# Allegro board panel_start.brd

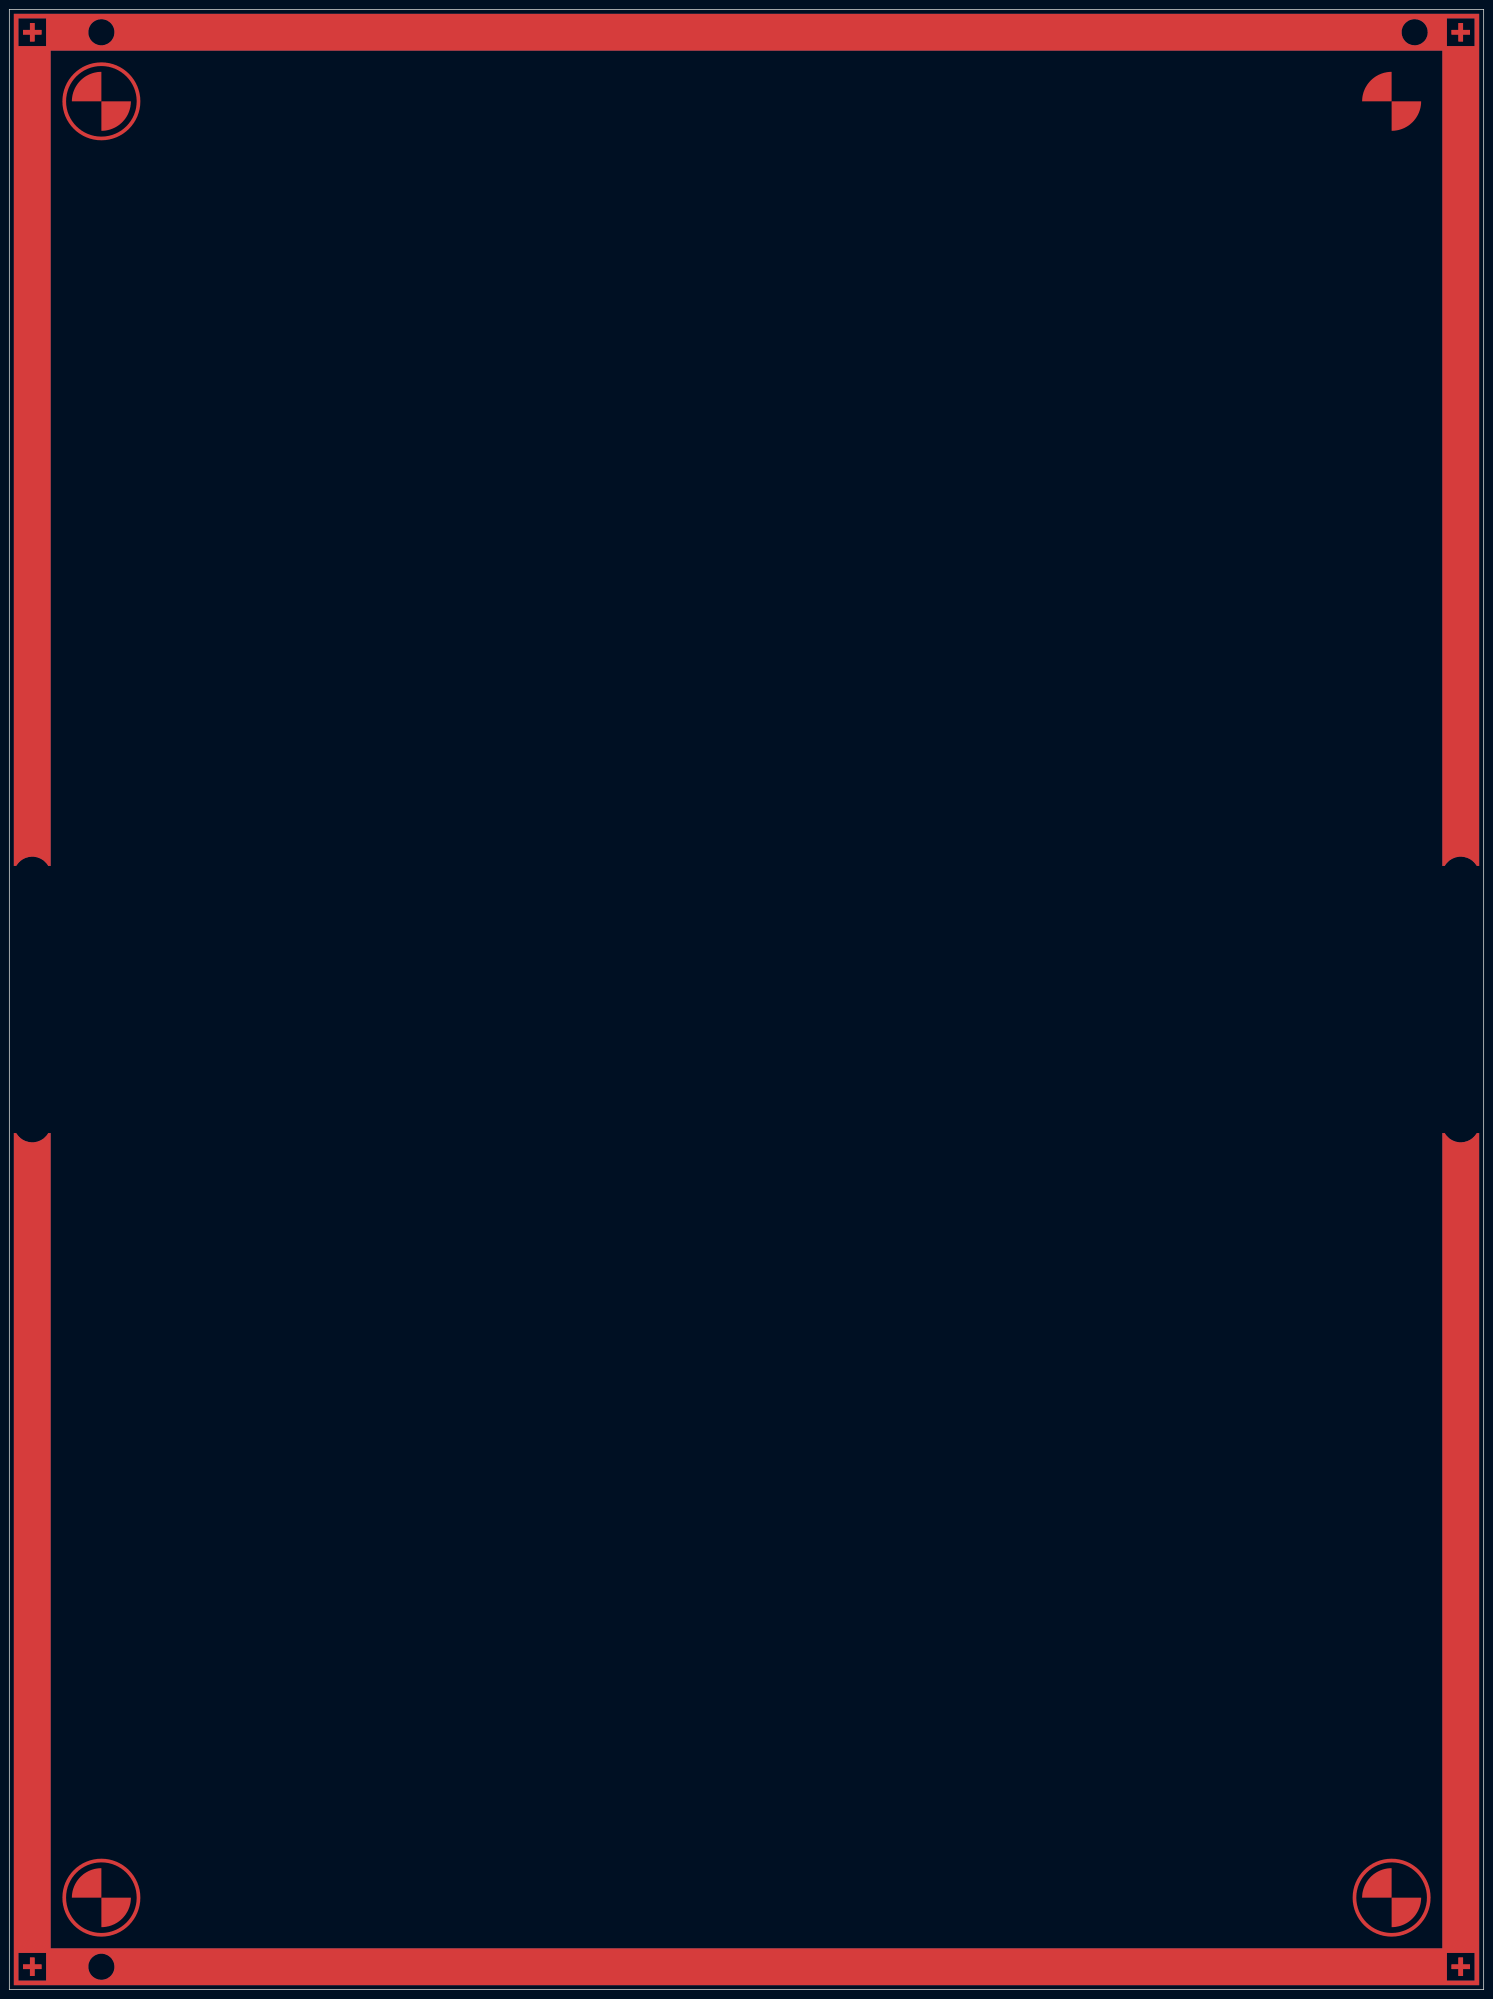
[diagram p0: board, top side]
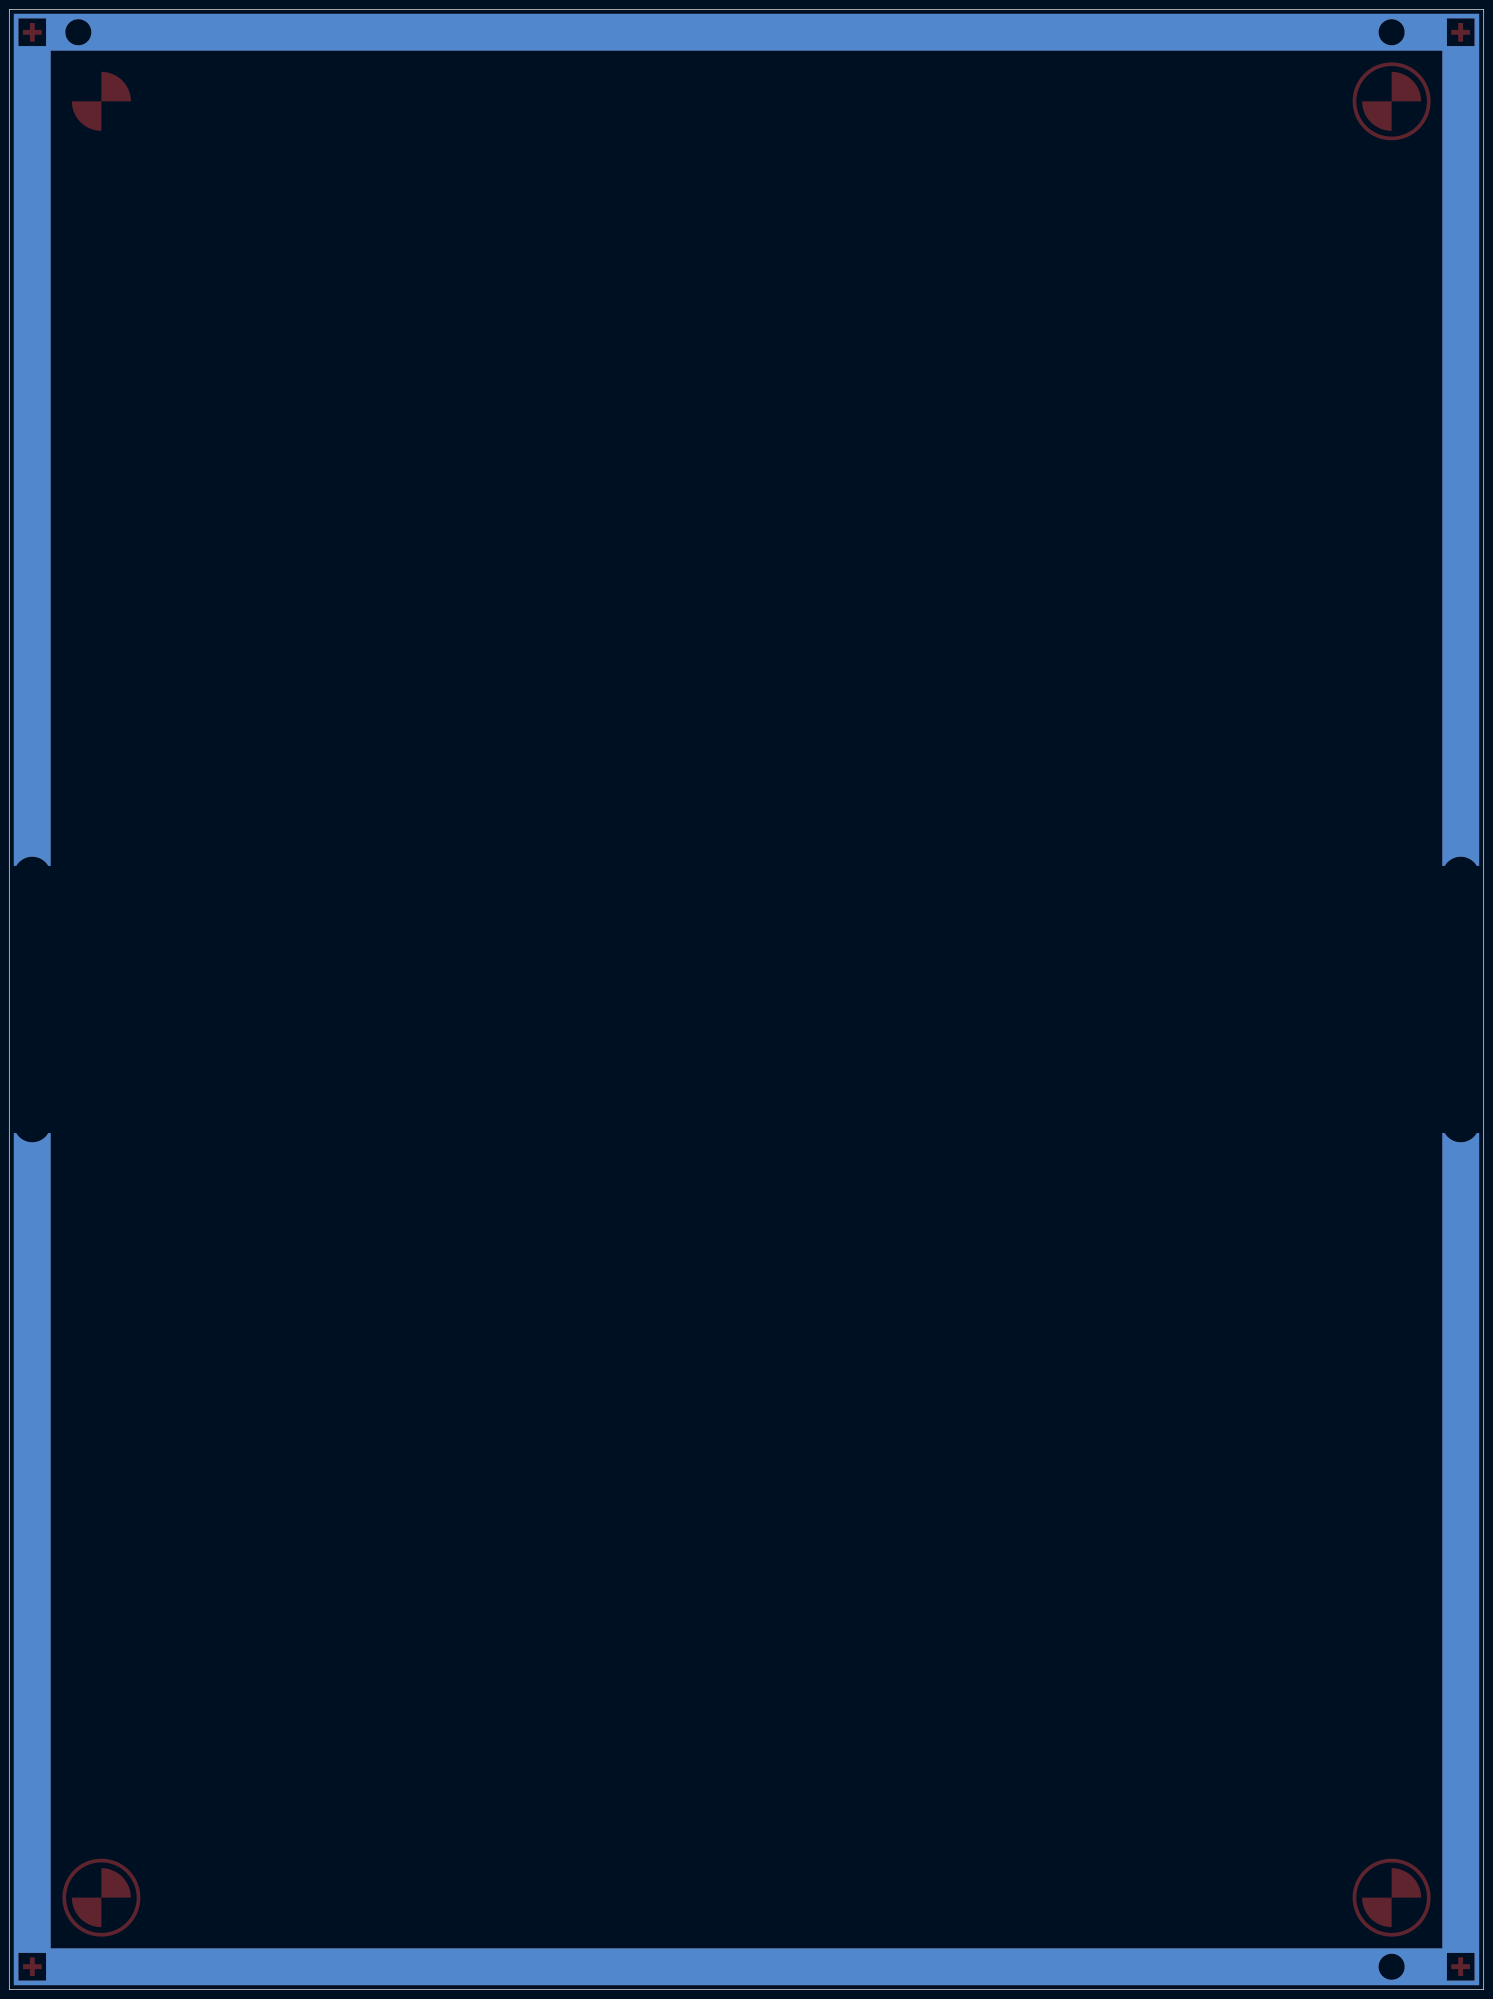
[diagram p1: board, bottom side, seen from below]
Outline 320 x 430 mm; copper layers: TOP, L02, L03, BOTTOM. Coordinates in mm from the lower left corner of the outline.

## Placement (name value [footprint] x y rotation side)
NOREF  -  []  320 0 90 top
NOREF#2  -  []  0 430 0 top
NOREF#3  -  []  315 425 0 top
NOREF#4  -  []  20 5 90 top
NOREF#5  -  []  315 425 90 top
NOREF#6  -  [unnamed#2]  0 0 0 top
NOREF#7  -  []  20 425 0 top
NOREF#8  -  []  315 5 0 top
NOREF#9  -  []  0 0 90 top

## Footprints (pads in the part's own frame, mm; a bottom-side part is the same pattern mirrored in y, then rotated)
unnamed#2
  custom 1x1 smd: (5,425) (5,425) (5,5) (5,5) (315,425) (315,425) (315,5) (315,5)
  round 0 hole 2.8 unplated: (20,425) (20,5) (305,425)

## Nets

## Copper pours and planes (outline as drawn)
Net_13370 on BOTTOM (solid shape): outline of 237 points within 1,1 319,186
Net_13371 on BOTTOM (solid shape): outline of 358 points within 1,244 319,429
Net_13372 on TOP (solid shape): outline of 237 points within 1,1 319,186
Net_13373 on TOP (solid shape): outline of 358 points within 1,244 319,429

Small or netless copper shapes (teardrops, artwork): 8 on TOP
